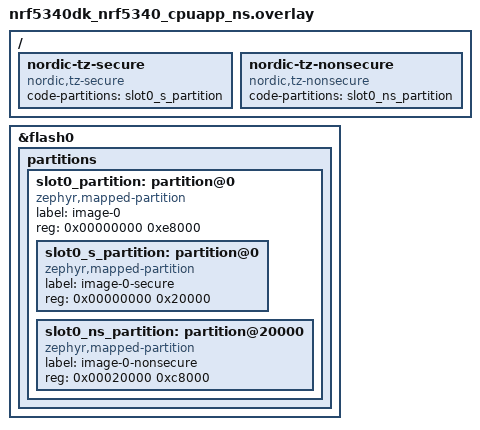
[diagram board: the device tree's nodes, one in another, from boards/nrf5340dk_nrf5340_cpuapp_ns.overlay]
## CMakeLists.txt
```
#
# Copyright (c) 2021 Nordic Semiconductor ASA
#
# SPDX-License-Identifier: LicenseRef-Nordic-5-Clause
#
cmake_minimum_required(VERSION 3.20.0)

find_package(Zephyr REQUIRED HINTS $ENV{ZEPHYR_BASE})
project(mesh_silvair_enocean)

# NORDIC SDK APP START
target_sources(app PRIVATE
  src/main.c
  src/model_handler.c
)
target_include_directories(app PRIVATE include)
# NORDIC SDK APP END
```

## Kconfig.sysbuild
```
#
# Copyright (c) 2023 Nordic Semiconductor
#
# SPDX-License-Identifier: LicenseRef-Nordic-5-Clause
#

config NRF_DEFAULT_IPC_RADIO
	default y

config PARTITION_MANAGER
	default n

source "share/sysbuild/Kconfig"
```

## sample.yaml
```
sample:
  description: Bluetooth Mesh Silvair EnOcean sample
  name: Bluetooth Mesh Silvair EnOcean
common:
  tags:
    - bluetooth
    - ci_build
    - sysbuild
    - ci_samples_bluetooth
tests:
  sample.bluetooth.mesh.silvair_enocean:
    sysbuild: true
    build_only: true
    integration_platforms:
      - nrf54l15dk/nrf54l15/cpuapp
    platform_allow:
      - nrf5340dk/nrf5340/cpuapp
      - nrf5340dk/nrf5340/cpuapp/ns
      - nrf54l15dk/nrf54l15/cpuapp
      - nrf54l15dk/nrf54l10/cpuapp
      - nrf54l15dk/nrf54l05/cpuapp
      - nrf54lm20dk/nrf54lm20a/cpuapp
  sample.bluetooth.mesh.silvair_enocean.settings_ext_flash:
    sysbuild: true
    build_only: true
    integration_platforms:
      - nrf54l15dk/nrf54l15/cpuapp
    platform_allow:
      - nrf54l15dk/nrf54l15/cpuapp
      - nrf54l15dk/nrf54l10/cpuapp
      - nrf54l15dk/nrf54l05/cpuapp
    extra_args: FILE_SUFFIX=settings_ext_flash
```

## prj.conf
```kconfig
#
# Copyright (c) 2021 Nordic Semiconductor ASA
#
# SPDX-License-Identifier: LicenseRef-Nordic-5-Clause
#
CONFIG_NCS_SAMPLES_DEFAULTS=y

# Deferred logging helps improve LPN power consumption
# when friendship is established.
CONFIG_LOG_MODE_DEFERRED=y

# General configuration
CONFIG_NCS_APPLICATION_BOOT_BANNER_STRING="Mesh Silvair EnOcean"
CONFIG_SYSTEM_WORKQUEUE_STACK_SIZE=2048
CONFIG_FLASH=y
CONFIG_FLASH_MAP=y
CONFIG_NVS=y
CONFIG_SETTINGS=y
CONFIG_NVS_LOOKUP_CACHE=y
CONFIG_SETTINGS_NVS_NAME_CACHE=y
CONFIG_HWINFO=y
CONFIG_DK_LIBRARY=y
CONFIG_SOC_FLASH_NRF_PARTIAL_ERASE=y

# Bluetooth configuration
CONFIG_BT=y
CONFIG_BT_COMPANY_ID=0x0136
CONFIG_BT_DEVICE_NAME="Mesh Silvair EnOcean"
CONFIG_BT_L2CAP_TX_BUF_COUNT=8
CONFIG_BT_OBSERVER=y
CONFIG_BT_PERIPHERAL=y
CONFIG_BT_SETTINGS=y
CONFIG_BT_HOST_CCM=y

# Disable unused Bluetooth features
CONFIG_BT_CTLR_LE_ENC=n
CONFIG_BT_PHY_UPDATE=n
CONFIG_BT_CTLR_CHAN_SEL_2=n
CONFIG_BT_CTLR_MIN_USED_CHAN=n
CONFIG_BT_CTLR_PRIVACY=n

# Bluetooth Mesh configuration
CONFIG_BT_MESH=y
CONFIG_BT_MESH_RELAY=y
CONFIG_BT_MESH_NETWORK_TRANSMIT_COUNT=0
CONFIG_BT_MESH_FRIEND=y
CONFIG_BT_MESH_ADV_BUF_COUNT=64
CONFIG_BT_MESH_TX_SEG_MAX=32
CONFIG_BT_MESH_PB_GATT=y
CONFIG_BT_MESH_GATT_PROXY=y
CONFIG_BT_MESH_PROXY_USE_DEVICE_NAME=y
CONFIG_BT_MESH_DK_PROV=y

# Bluetooth Mesh models
CONFIG_BT_MESH_DTT_SRV=y
CONFIG_BT_MESH_SILVAIR_ENOCEAN_SRV=y
CONFIG_BT_MESH_SILVAIR_ENOCEAN_AUTO_COMMISSION=y

CONFIG_LTO=y
CONFIG_ISR_TABLES_LOCAL_DECLARATION=y
```

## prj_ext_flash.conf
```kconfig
##
# Copyright (c) 2025 Nordic Semiconductor ASA
# SPDX-License-Identifier: LicenseRef-Nordic-5-Clause

CONFIG_NORDIC_QSPI_NOR=y
CONFIG_SETTINGS=y
CONFIG_SETTINGS_NVS=y
```

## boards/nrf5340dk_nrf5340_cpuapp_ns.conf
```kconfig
#
# Copyright (c) 2023 Nordic Semiconductor ASA
#
# SPDX-License-Identifier: LicenseRef-Nordic-5-Clause
#
################################################################################
# Application overlay - nrf5340dk non secure image

CONFIG_TFM_PROFILE_TYPE_MINIMAL=y

CONFIG_SOC_FLASH_NRF_PARTIAL_ERASE=n
```

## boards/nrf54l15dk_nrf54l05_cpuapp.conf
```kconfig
#
# Copyright (c) 2024 Nordic Semiconductor ASA
#
# SPDX-License-Identifier: LicenseRef-Nordic-5-Clause
#
################################################################################
# Application overlay - nrf54l05

CONFIG_SOC_FLASH_NRF_PARTIAL_ERASE=n
CONFIG_NVS=n
CONFIG_NVS_LOOKUP_CACHE=n
CONFIG_SETTINGS_NVS_NAME_CACHE=n
CONFIG_ZMS=y
CONFIG_SETTINGS_ZMS_CUSTOM_SECTOR_COUNT=y
CONFIG_SETTINGS_ZMS_SECTOR_COUNT=8
CONFIG_ZMS_LOOKUP_CACHE=y
CONFIG_ZMS_LOOKUP_CACHE_SIZE=512
CONFIG_SETTINGS_ZMS_NAME_CACHE=y
CONFIG_SETTINGS_ZMS_NAME_CACHE_SIZE=512
CONFIG_ZMS_LOOKUP_CACHE_FOR_SETTINGS=y
CONFIG_SYSTEM_WORKQUEUE_STACK_SIZE=4096
CONFIG_BT_RX_STACK_SIZE=5120
```

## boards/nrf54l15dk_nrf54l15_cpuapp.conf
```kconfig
#
# Copyright (c) 2024 Nordic Semiconductor ASA
#
# SPDX-License-Identifier: LicenseRef-Nordic-5-Clause
#
################################################################################
# Application overlay - nrf54l15

CONFIG_SOC_FLASH_NRF_PARTIAL_ERASE=n
CONFIG_NVS=n
CONFIG_NVS_LOOKUP_CACHE=n
CONFIG_SETTINGS_NVS_NAME_CACHE=n
CONFIG_ZMS=y
CONFIG_SETTINGS_ZMS_SECTOR_COUNT=8
CONFIG_ZMS_LOOKUP_CACHE=y
CONFIG_ZMS_LOOKUP_CACHE_SIZE=512
CONFIG_SETTINGS_ZMS_NAME_CACHE=y
CONFIG_SETTINGS_ZMS_NAME_CACHE_SIZE=512
CONFIG_ZMS_LOOKUP_CACHE_FOR_SETTINGS=y
CONFIG_SYSTEM_WORKQUEUE_STACK_SIZE=4096
CONFIG_BT_RX_STACK_SIZE=5120
```

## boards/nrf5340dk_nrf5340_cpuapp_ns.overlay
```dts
/*
 * Copyright (c) 2026 Nordic Semiconductor ASA
 *
 * SPDX-License-Identifier: LicenseRef-Nordic-5-Clause
 */

/* Rebalance secure/non-secure subpartitions to fit larger mesh sample image.
 * MCUboot is removed; slot0 starts at 0x0 and spans 928 KB (0xe8000).
 * Secure: 128 KB, Non-secure: 800 KB.
 */

/delete-node/ &boot_partition;
/delete-node/ &slot0_partition;

&flash0 {
	partitions {
		slot0_partition: partition@0 {
			compatible = "zephyr,mapped-partition";
			label = "image-0";
			reg = <0x00000000 0xe8000>;
			ranges = <0x0 0x0 0xe8000>;
			#address-cells = <1>;
			#size-cells = <1>;

			slot0_s_partition: partition@0 {
				compatible = "zephyr,mapped-partition";
				label = "image-0-secure";
				reg = <0x00000000 0x20000>;
			};

			slot0_ns_partition: partition@20000 {
				compatible = "zephyr,mapped-partition";
				label = "image-0-nonsecure";
				reg = <0x00020000 0xc8000>;
			};
		};
	};
};

/ {
	/delete-node/ nordic-tz-secure;
	/delete-node/ nordic-tz-nonsecure;

	nordic-tz-secure {
		compatible = "nordic,tz-secure";
		code-partitions = <&slot0_s_partition>;
	};

	nordic-tz-nonsecure {
		compatible = "nordic,tz-nonsecure";
		code-partitions = <&slot0_ns_partition>;
	};
};
```

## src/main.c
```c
/*
 * Copyright (c) 2021 Nordic Semiconductor ASA
 *
 * SPDX-License-Identifier: LicenseRef-Nordic-5-Clause
 */

/** @file
 *  @brief Nordic mesh Silvair EnOcean sample
 */
#include <zephyr/bluetooth/bluetooth.h>
#include <bluetooth/mesh/models.h>
#include <bluetooth/mesh/dk_prov.h>
#include <dk_buttons_and_leds.h>
#include "model_handler.h"

static void bt_ready(int err)
{
	if (err) {
		printk("Bluetooth init failed (err %d)\n", err);
		return;
	}

	printk("Bluetooth initialized\n");

	err = dk_leds_init();
	if (err) {
		printk("Initializing LEDs failed (err %d)\n", err);
		return;
	}

	err = dk_buttons_init(NULL);
	if (err) {
		printk("Initializing buttons failed (err %d)\n", err);
		return;
	}

	err = bt_mesh_init(bt_mesh_dk_prov_init(), model_handler_init());
	if (err) {
		printk("Initializing mesh failed (err %d)\n", err);
		return;
	}

	if (IS_ENABLED(CONFIG_SETTINGS)) {
		settings_load();
	}

	/* This will be a no-op if settings_load() loaded provisioning info */
	bt_mesh_prov_enable(BT_MESH_PROV_ADV | BT_MESH_PROV_GATT);

	printk("Mesh initialized\n");
}

int main(void)
{
	int err;

	printk("Initializing...\n");

	err = bt_enable(bt_ready);
	if (err) {
		printk("Bluetooth init failed (err %d)\n", err);
	}

	return 0;
}
```

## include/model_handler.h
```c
/*
 * Copyright (c) 2021 Nordic Semiconductor ASA
 *
 * SPDX-License-Identifier: LicenseRef-Nordic-5-Clause
 */

/**
 * @file
 * @brief Model handler
 */

#ifndef MODEL_HANDLER_H__
#define MODEL_HANDLER_H__

#include <zephyr/bluetooth/mesh.h>

#ifdef __cplusplus
extern "C" {
#endif

const struct bt_mesh_comp *model_handler_init(void);

#ifdef __cplusplus
}
#endif

#endif /* MODEL_HANDLER_H__ */
```

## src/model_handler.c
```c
/*
 * Copyright (c) 2021 Nordic Semiconductor ASA
 *
 * SPDX-License-Identifier: LicenseRef-Nordic-5-Clause
 */

/**
 * @file
 * @brief Model handler for the Silvair EnOcean sample.
 *
 * Instantiates a Silvair EnOcean Proxy Server model on the devkit, as well as
 * the standard Config and Health Server models. Handles all application
 * behavior related to the models.
 */
#include <zephyr/bluetooth/bluetooth.h>
#include <bluetooth/mesh/models.h>
#include <bluetooth/mesh/vnd/silvair_enocean_srv.h>
#include <dk_buttons_and_leds.h>
#include "model_handler.h"

static struct bt_mesh_dtt_srv dtt_srv = BT_MESH_DTT_SRV_INIT(NULL);

/* Silvair Enocean Proxy behavior */
static void onoff_status(struct bt_mesh_onoff_cli *cli,
			 struct bt_mesh_msg_ctx *ctx,
			 const struct bt_mesh_onoff_status *status);

static void level_status(struct bt_mesh_lvl_cli *cli,
			 struct bt_mesh_msg_ctx *ctx,
			 const struct bt_mesh_lvl_status *status);

struct bt_mesh_silvair_enocean_srv silvair_enocean = {
	.buttons[0 ... 1] = { .onoff = BT_MESH_ONOFF_CLI_INIT(&onoff_status),
			      .lvl = BT_MESH_LVL_CLI_INIT(&level_status), },
};

static void onoff_status(struct bt_mesh_onoff_cli *cli,
			 struct bt_mesh_msg_ctx *ctx,
			 const struct bt_mesh_onoff_status *status)
{
	struct bt_mesh_silvair_enocean_button *button =
		CONTAINER_OF(cli, struct bt_mesh_silvair_enocean_button, onoff);
	int index = button - &silvair_enocean.buttons[0];

	dk_set_led(index, status->present_on_off);

	printk("Button %d: Received onoff response: %s\n", index + 1,
	       status->present_on_off ? "on" : "off");
}

static void level_status(struct bt_mesh_lvl_cli *cli,
			 struct bt_mesh_msg_ctx *ctx,
			 const struct bt_mesh_lvl_status *status)
{
	struct bt_mesh_silvair_enocean_button *button =
		CONTAINER_OF(cli, struct bt_mesh_silvair_enocean_button, lvl);
	int index = button - &silvair_enocean.buttons[0];

	dk_set_led(index, status->current != BT_MESH_LVL_MIN);

	printk("Button %d: Received level response: current: %d\n", index + 1,
		status->current);
}

/* Set up a repeating delayed work to blink the DK's LEDs when attention is
 * requested.
 */
static struct k_work_delayable attention_blink_work;
static bool attention;

static void attention_blink(struct k_work *work)
{
	static int idx;
	const uint8_t pattern[] = {
		BIT(0) | BIT(1),
		BIT(1) | BIT(2),
		BIT(2) | BIT(3),
		BIT(3) | BIT(0),
	};

	if (attention) {
		dk_set_leds(pattern[idx++ % ARRAY_SIZE(pattern)]);
		k_work_reschedule(&attention_blink_work, K_MSEC(30));
	} else {
		dk_set_leds(DK_NO_LEDS_MSK);
	}
}

static void attention_on(const struct bt_mesh_model *mod)
{
	attention = true;
	k_work_reschedule(&attention_blink_work, K_NO_WAIT);
}

static void attention_off(const struct bt_mesh_model *mod)
{
	/* Will stop rescheduling blink timer */
	attention = false;
}

static const struct bt_mesh_health_srv_cb health_srv_cb = {
	.attn_on = attention_on,
	.attn_off = attention_off,
};

static struct bt_mesh_health_srv health_srv = {
	.cb = &health_srv_cb,
};

BT_MESH_HEALTH_PUB_DEFINE(health_pub, 0);

static struct bt_mesh_elem elements[] = {
	BT_MESH_ELEM(1,
		BT_MESH_MODEL_LIST(BT_MESH_MODEL_CFG_SRV,
				   BT_MESH_MODEL_HEALTH_SRV(&health_srv,
							    &health_pub),
				   BT_MESH_MODEL_DTT_SRV(&dtt_srv),
				   BT_MESH_MODEL_SILVAIR_ENOCEAN_BUTTON(
					&silvair_enocean, 0)),
		BT_MESH_MODEL_LIST(BT_MESH_MODEL_SILVAIR_ENOCEAN_SRV(
					&silvair_enocean))),
	BT_MESH_ELEM(2,
		BT_MESH_MODEL_LIST(BT_MESH_MODEL_SILVAIR_ENOCEAN_BUTTON(
					&silvair_enocean, 1)),
		BT_MESH_MODEL_NONE),
};

static const struct bt_mesh_comp comp = {
	.cid = CONFIG_BT_COMPANY_ID,
	.elem = elements,
	.elem_count = ARRAY_SIZE(elements),
};

const struct bt_mesh_comp *model_handler_init(void)
{
	k_work_init_delayable(&attention_blink_work, attention_blink);

	return &comp;
}
```
